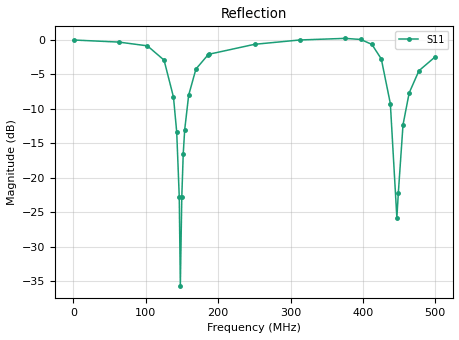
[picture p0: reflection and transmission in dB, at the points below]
# Hz S RI R 50.0
! written by SimSmith version 18.3h
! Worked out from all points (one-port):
!   1000 points, 100 kHz to 500 MHz, reference 50 ohm
!   lowest |S11| = -35.6 dB at 147.7 MHz (marker M1), VSWR 1.03, Z = 48.5 - j0.703 ohm
!   |S11| at or under -10 dB: 140.1 MHz to 156.5 MHz (16.37 MHz wide, 11 % of centre); 438.8 MHz to 458.9 MHz (20.09 MHz wide, 4.48 % of centre)
!   S11 on the Smith chart (normalised r, x): 100 kHz: open; 138.2 MHz: 0.86, -0.76; 185.7 MHz: 2.06, +3.40; 412.4 MHz: 0.20, -2.11; 455.5 MHz: 1.43, +0.42; 500 MHz: 4.96, +3.27
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100000  1 -0.000436
6.265005e7  0.9406 -0.2185
1.021817e8  0.7907 -0.4443
1.252001e8  0.4376 -0.5651
1.382105e8  0.0799 -0.3776
1.427141e8  -0.00301 -0.2149
1.462169e8  -0.0207 -0.0698
1.477181e8  -0.0149 -0.00724
1.497197e8  0.00456 0.0725
1.517213e8  0.0363 0.1455
1.537229e8  0.0776 0.2095
1.592273e8  0.2162 0.3341
1.692353e8  0.4674 0.4007
1.857485e8  0.7072 0.3247
1.877502e8  0.7249 0.3126
2.503002e8  0.9277 0.0734
3.128503e8  0.9898 -0.1442
3.754003e8  0.9352 -0.4257
3.969175e8  0.8144 -0.5956
4.124299e8  0.5937 -0.7147
4.254403e8  0.2607 -0.6807
4.379504e8  -8.83e-05 -0.346
4.469576e8  0.0398 -0.0324
4.489592e8  0.0747 0.0212
4.554644e8  0.2002 0.1378
4.639712e8  0.3542 0.2136
4.77482e8  0.5546 0.2259
5e8  0.7422 0.1414
